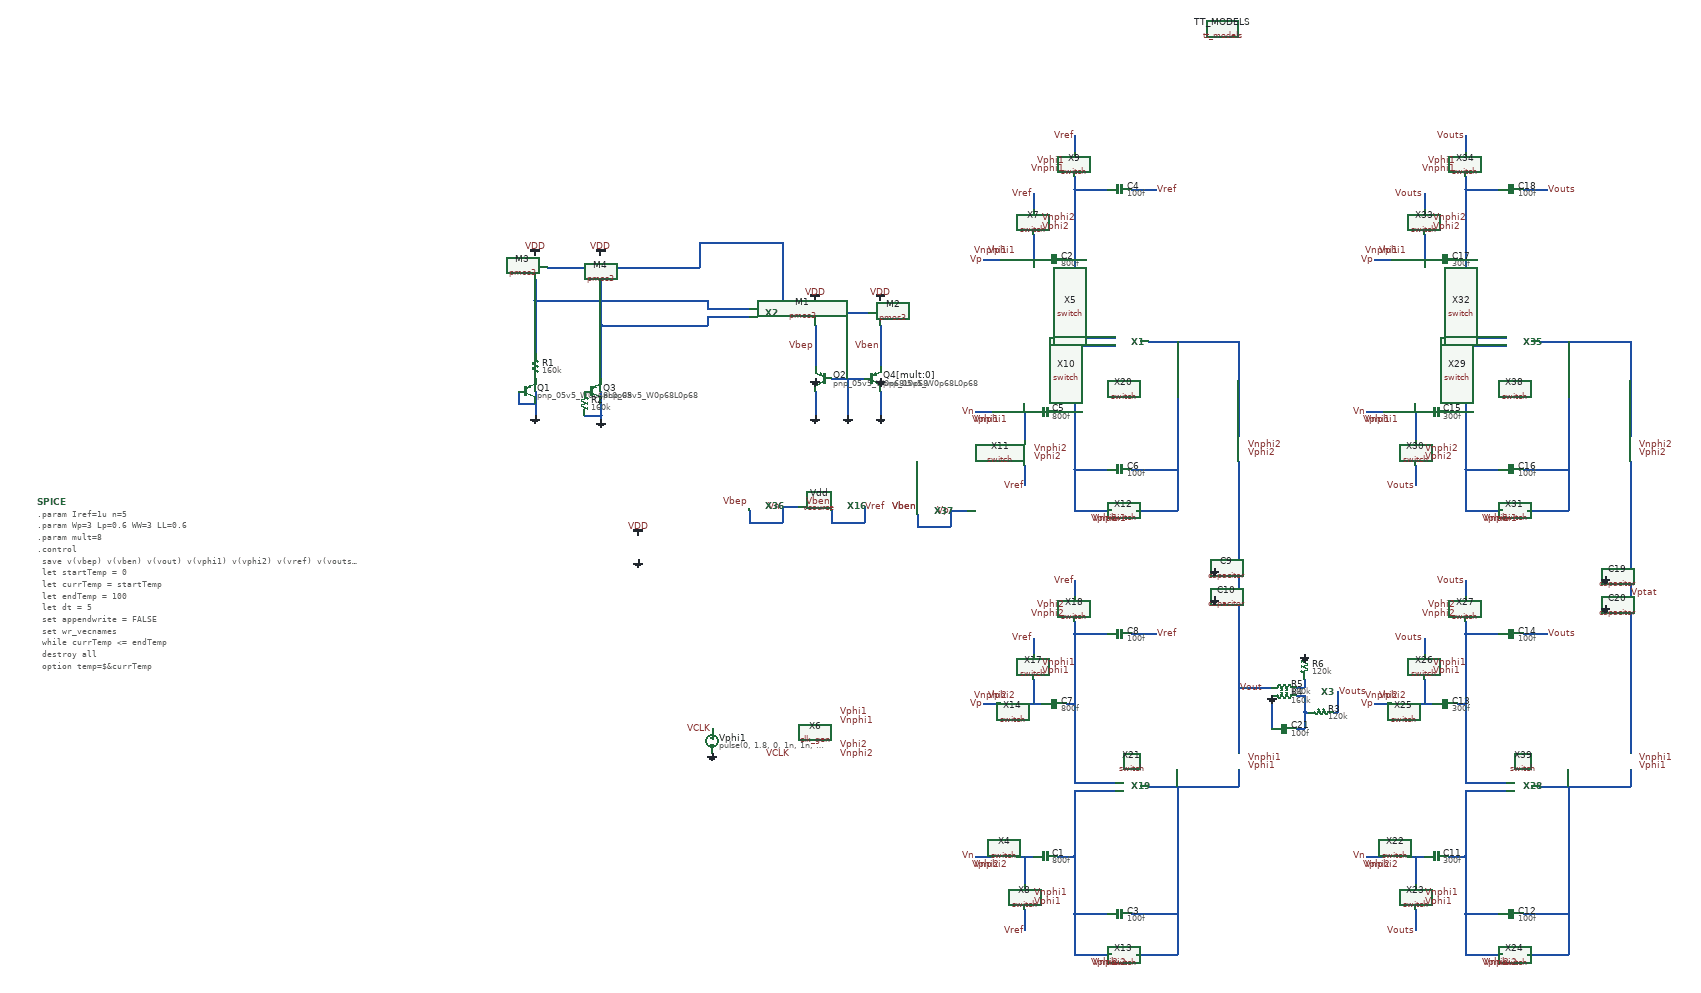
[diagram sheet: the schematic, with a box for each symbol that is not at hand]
v {xschem version=2.9.9 file_version=1.2 }
G {}
K {}
V {}
S {}
E {}
N 610 -70 670 -70 { lab=#net1}
N 410 10 410 40 { lab=Vnn}
N -60 -40 -60 -10 { lab=Vben}
N -60 -110 -60 -40 { lab=Vben}
N -220 -110 -220 -10 { lab=Vbep}
N -300 -140 -250 -140 { lab=#net2}
N -250 -140 -90 -140 { lab=#net2}
N -900 50 -900 80 { lab=GND}
N -940 50 -940 80 { lab=GND}
N -940 80 -900 80 { lab=GND}
N -900 80 -900 110 { lab=GND}
N -740 50 -740 80 { lab=GND}
N -740 80 -740 110 { lab=GND}
N -780 110 -740 110 { lab=GND}
N -740 110 -740 120 { lab=GND}
N -740 -110 -740 20 { lab=#net3}
N -740 -110 -480 -110 { lab=#net3}
N -900 -170 -480 -170 { lab=#net4}
N -900 -170 -900 -40 { lab=#net4}
N -500 -310 -500 -250 { lab=#net2}
N -500 -310 -300 -310 { lab=#net2}
N -300 -310 -300 -140 { lab=#net2}
N -870 -250 -710 -250 { lab=#net2}
N -710 -250 -500 -250 { lab=#net2}
N -740 -220 -740 -110 { lab=#net3}
N -900 -220 -900 -170 { lab=#net4}
N -180 20 -100 20 { lab=GND}
N -60 50 -60 110 { lab=GND}
N -220 50 -220 110 { lab=GND}
N -140 20 -140 80 { lab=GND}
N -140 80 -140 110 { lab=GND}
N 410 100 410 240 { lab=Vnn}
N 410 240 490 240 { lab=Vnn}
N 410 340 500 340 { lab=Vnn}
N 410 240 410 340 { lab=Vnn}
N 660 70 660 240 { lab=#net1}
N 550 240 660 240 { lab=#net1}
N 560 340 660 340 { lab=#net1}
N 660 240 660 340 { lab=#net1}
N 290 100 290 170 { lab=#net5}
N 270 100 310 100 { lab=#net5}
N 170 100 210 100 { lab=Vn}
N 290 230 290 280 { lab=Vref}
N 370 100 410 100 { lab=Vnn}
N 410 40 410 100 { lab=Vnn}
N 660 -70 660 70 { lab=#net1}
N 410 -440 410 -270 { lab=Vpp}
N 410 -440 490 -440 { lab=Vpp}
N 410 -470 410 -440 { lab=Vpp}
N 310 -330 310 -270 { lab=#net6}
N 290 -270 330 -270 { lab=#net6}
N 190 -270 230 -270 { lab=Vp}
N 550 -440 610 -440 { lab=Vref}
N 410 -570 410 -530 { lab=Vref}
N 310 -430 310 -390 { lab=Vref}
N 410 -40 410 10 { lab=Vnn}
N 410 -270 410 -100 { lab=Vpp}
N 390 -270 410 -270 { lab=Vpp}
N 410 -60 410 -40 { lab=Vnn}
N 410 -100 410 -80 { lab=Vpp}
N 590 -70 610 -70 { lab=#net1}
N -480 -150 -380 -150 { lab=#net4}
N -480 -170 -480 -150 { lab=#net4}
N -480 -130 -480 -110 { lab=#net3}
N -480 -130 -380 -130 { lab=#net3}
N 410 -60 510 -60 { lab=Vnn}
N 410 -80 510 -80 { lab=Vpp}
N -180 340 -180 370 { lab=Vref}
N -180 370 -100 370 { lab=Vref}
N -100 330 -100 370 { lab=Vref}
N 670 -70 720 -70 { lab=#net1}
N 610 1010 670 1010 { lab=#net7}
N 410 1090 410 1120 { lab=#net8}
N 410 1180 410 1320 { lab=#net8}
N 410 1320 490 1320 { lab=#net8}
N 410 1420 500 1420 { lab=#net8}
N 410 1320 410 1420 { lab=#net8}
N 660 1150 660 1320 { lab=#net7}
N 550 1320 660 1320 { lab=#net7}
N 560 1420 660 1420 { lab=#net7}
N 660 1320 660 1420 { lab=#net7}
N 290 1180 290 1250 { lab=#net9}
N 270 1180 310 1180 { lab=#net9}
N 170 1180 210 1180 { lab=Vn}
N 290 1310 290 1360 { lab=Vref}
N 370 1180 410 1180 { lab=#net8}
N 410 1120 410 1180 { lab=#net8}
N 660 1010 660 1150 { lab=#net7}
N 410 640 410 810 { lab=#net10}
N 410 640 490 640 { lab=#net10}
N 410 610 410 640 { lab=#net10}
N 310 750 310 810 { lab=#net11}
N 290 810 330 810 { lab=#net11}
N 190 810 230 810 { lab=Vp}
N 550 640 610 640 { lab=Vref}
N 410 510 410 550 { lab=Vref}
N 310 650 310 690 { lab=Vref}
N 410 1040 410 1090 { lab=#net8}
N 410 810 410 980 { lab=#net10}
N 390 810 410 810 { lab=#net10}
N 410 1020 410 1040 { lab=#net8}
N 410 980 410 1000 { lab=#net10}
N 590 1010 610 1010 { lab=#net7}
N 410 1020 510 1020 { lab=#net8}
N 410 1000 510 1000 { lab=#net10}
N 720 -70 810 -70 { lab=#net1}
N 810 -70 810 160 { lab=#net1}
N 810 220 810 810 { lab=Vout}
N 720 1010 810 1010 { lab=#net7}
N 810 970 810 1010 { lab=#net7}
N 810 810 810 930 { lab=Vout}
N 1560 1010 1620 1010 { lab=#net12}
N 1360 1090 1360 1120 { lab=#net13}
N 1360 1180 1360 1320 { lab=#net13}
N 1360 1320 1440 1320 { lab=#net13}
N 1360 1420 1450 1420 { lab=#net13}
N 1360 1320 1360 1420 { lab=#net13}
N 1610 1150 1610 1320 { lab=#net12}
N 1500 1320 1610 1320 { lab=#net12}
N 1510 1420 1610 1420 { lab=#net12}
N 1610 1320 1610 1420 { lab=#net12}
N 1240 1180 1240 1250 { lab=#net14}
N 1220 1180 1260 1180 { lab=#net14}
N 1120 1180 1160 1180 { lab=Vn}
N 1240 1310 1240 1360 { lab=Vouts}
N 1320 1180 1360 1180 { lab=#net13}
N 1360 1120 1360 1180 { lab=#net13}
N 1610 1010 1610 1150 { lab=#net12}
N 1360 640 1360 810 { lab=#net15}
N 1360 640 1440 640 { lab=#net15}
N 1360 610 1360 640 { lab=#net15}
N 1260 750 1260 810 { lab=#net16}
N 1240 810 1280 810 { lab=#net16}
N 1140 810 1180 810 { lab=Vp}
N 1500 640 1560 640 { lab=Vouts}
N 1360 510 1360 550 { lab=Vouts}
N 1260 650 1260 690 { lab=Vouts}
N 1360 1040 1360 1090 { lab=#net13}
N 1360 810 1360 980 { lab=#net15}
N 1340 810 1360 810 { lab=#net15}
N 1360 1020 1360 1040 { lab=#net13}
N 1360 980 1360 1000 { lab=#net15}
N 1540 1010 1560 1010 { lab=#net12}
N 1360 1020 1460 1020 { lab=#net13}
N 1360 1000 1460 1000 { lab=#net15}
N 670 1010 720 1010 { lab=#net7}
N 1560 -70 1620 -70 { lab=#net17}
N 1360 10 1360 40 { lab=#net18}
N 1360 100 1360 240 { lab=#net18}
N 1360 240 1440 240 { lab=#net18}
N 1360 340 1450 340 { lab=#net18}
N 1360 240 1360 340 { lab=#net18}
N 1610 70 1610 240 { lab=#net17}
N 1500 240 1610 240 { lab=#net17}
N 1510 340 1610 340 { lab=#net17}
N 1610 240 1610 340 { lab=#net17}
N 1240 100 1240 170 { lab=#net19}
N 1220 100 1260 100 { lab=#net19}
N 1120 100 1160 100 { lab=Vn}
N 1240 230 1240 280 { lab=Vouts}
N 1320 100 1360 100 { lab=#net18}
N 1360 40 1360 100 { lab=#net18}
N 1610 -70 1610 70 { lab=#net17}
N 1360 -440 1360 -270 { lab=#net20}
N 1360 -440 1440 -440 { lab=#net20}
N 1360 -470 1360 -440 { lab=#net20}
N 1260 -330 1260 -270 { lab=#net21}
N 1240 -270 1280 -270 { lab=#net21}
N 1140 -270 1180 -270 { lab=Vp}
N 1500 -440 1560 -440 { lab=Vouts}
N 1360 -570 1360 -530 { lab=Vouts}
N 1260 -430 1260 -390 { lab=Vouts}
N 1360 -40 1360 10 { lab=#net18}
N 1360 -270 1360 -100 { lab=#net20}
N 1340 -270 1360 -270 { lab=#net20}
N 1360 -60 1360 -40 { lab=#net18}
N 1360 -100 1360 -80 { lab=#net20}
N 1540 -70 1560 -70 { lab=#net17}
N 1360 -60 1460 -60 { lab=#net18}
N 1360 -80 1460 -80 { lab=#net20}
N 1620 -70 1670 -70 { lab=#net17}
N 1670 -70 1760 -70 { lab=#net17}
N 1760 -70 1760 160 { lab=#net17}
N 1760 220 1760 810 { lab=Vptat}
N 1760 970 1760 1010 { lab=#net12}
N 1760 810 1760 930 { lab=Vptat}
N 1620 1010 1760 1010 { lab=#net12}
N -300 330 -260 330 { lab=Vn}
N 110 340 150 340 { lab=Vp}
N -380 340 -380 370 { lab=Vn}
N -380 370 -300 370 { lab=Vn}
N -300 330 -300 370 { lab=Vn}
N 30 350 30 380 { lab=Vp}
N 30 380 110 380 { lab=Vp}
N 110 340 110 380 { lab=Vp}
N 1050 780 1050 830 { lab=Vouts}
N 1040 830 1050 830 { lab=Vouts}
N 970 830 980 830 { lab=#net22}
N 970 790 970 830 { lab=#net22}
N 950 790 970 790 { lab=#net22}
N 810 770 890 770 { lab=Vout}
N 950 770 970 770 { lab=#net23}
N 970 750 970 770 { lab=#net23}
N 890 790 890 870 { lab=GND}
N 950 870 970 870 { lab=#net22}
N 970 830 970 870 { lab=#net22}
C {madvlsi/vsource.sym} -650 430 0 0 {name=Vdd
value=1.8}
C {madvlsi/vdd.sym} -650 400 0 0 {name=l3 lab=VDD}
C {madvlsi/gnd.sym} -650 460 0 0 {name=l4 lab=GND}
C {devices/code_shown.sym} -2110 320 0 0 {name=SPICE only_toplevel=false value=".param Iref=1u n=5 
.param Wp=3 Lp=0.6 WW=3 LL=0.6
.param mult=8
.control
  save v(vbep) v(vben) v(vout) v(vphi1) v(vphi2) v(vref) v(vouts) v(vptat)
  let startTemp = 0
  let currTemp = startTemp
  let endTemp = 100
  let dt = 5
  set appendwrite = FALSE
  set wr_vecnames
  while currTemp <= endTemp
    destroy all
    option temp=$&currTemp
    tran 1.2u 60u
    wrdata /home/madvlsi/Documents/MADVLSI-Final_Project/schematic/data/SCbandgap\{$&currTemp\}ptat.csv v(vbep) v(vben) v(vout) v(vphi1) v(vphi2) v(vref) v(vouts) v(vptat) currTemp
    let currTemp = currTemp + dt
    reset
  end
*plot v(Vout) 8.0*(v(Vbep)-v(Vben))+v(Vben)
*plot v(Vout) v(Vouts)
.endc
.OPTIONS ITL1=300  ITL2=100"}
C {sky130_fd_pr/pnp_05v5.sym} -200 20 0 1 {name=Q2
model=pnp_05v5_W0p68L0p68
spiceprefix=X
}
C {madvlsi/vdd.sym} -220 -170 0 0 {name=l2 lab=VDD}
C {madvlsi/vdd.sym} -60 -170 0 0 {name=l5 lab=VDD}
C {devices/lab_pin.sym} -220 -60 0 0 {name=l10 sig_type=std_logic lab=Vbep}
C {devices/lab_pin.sym} -60 -60 0 0 {name=l11 sig_type=std_logic lab=Vben}
C {madvlsi/pmos3.sym} -220 -140 0 0 {name=M1
L=Lp
W=Wp
body=VDD
nf=1
mult=mult
ad="'int((nf+1)/2) * W/nf * 0.29'" 
pd="'2*int((nf+1)/2) * (W/nf + 0.29)'"
as="'int((nf+2)/2) * W/nf * 0.29'" 
ps="'2*int((nf+2)/2) * (W/nf + 0.29)'"
nrd="'0.29 / W'" nrs="'0.29 / W'"
sa=0 sb=0 sd=0
model=pfet_01v8
spiceprefix=X
}
C {madvlsi/pmos3.sym} -60 -140 0 0 {name=M2
L=Lp
W=Wp
body=VDD
nf=1
mult=1
ad="'int((nf+1)/2) * W/nf * 0.29'" 
pd="'2*int((nf+1)/2) * (W/nf + 0.29)'"
as="'int((nf+2)/2) * W/nf * 0.29'" 
ps="'2*int((nf+2)/2) * (W/nf + 0.29)'"
nrd="'0.29 / W'" nrs="'0.29 / W'"
sa=0 sb=0 sd=0
model=pfet_01v8
spiceprefix=X
}
C {sky130_fd_pr/pnp_05v5.sym} -80 20 0 0 {name=Q4[mult:0]
model=pnp_05v5_W0p68L0p68
spiceprefix=X
}
C {sky130_fd_pr/pnp_05v5.sym} -920 50 0 0 {name=Q1
model=pnp_05v5_W0p68L0p68
spiceprefix=X
}
C {madvlsi/gnd.sym} -900 110 0 0 {name=l19 lab=GND}
C {sky130_fd_pr/pnp_05v5.sym} -760 50 0 0 {name=Q3
model=pnp_05v5_W0p68L0p68
spiceprefix=X
}
C {madvlsi/gnd.sym} -740 120 0 0 {name=l20 lab=GND}
C {madvlsi/resistor.sym} -900 -10 0 0 {name=R1
value=160k
m=1}
C {madvlsi/resistor.sym} -780 80 0 0 {name=R2
value=160k
m=mult}
C {madvlsi/pmos3.sym} -900 -250 0 1 {name=M3
L=Lp
W=Wp
body=VDD
nf=1
mult=1
ad="'int((nf+1)/2) * W/nf * 0.29'" 
pd="'2*int((nf+1)/2) * (W/nf + 0.29)'"
as="'int((nf+2)/2) * W/nf * 0.29'" 
ps="'2*int((nf+2)/2) * (W/nf + 0.29)'"
nrd="'0.29 / W'" nrs="'0.29 / W'"
sa=0 sb=0 sd=0
model=pfet_01v8
spiceprefix=X
}
C {madvlsi/pmos3.sym} -740 -250 0 1 {name=M4
L=Lp
W=Wp
body=VDD
nf=1
mult=mult
ad="'int((nf+1)/2) * W/nf * 0.29'" 
pd="'2*int((nf+1)/2) * (W/nf + 0.29)'"
as="'int((nf+2)/2) * W/nf * 0.29'" 
ps="'2*int((nf+2)/2) * (W/nf + 0.29)'"
nrd="'0.29 / W'" nrs="'0.29 / W'"
sa=0 sb=0 sd=0
model=pfet_01v8
spiceprefix=X
}
C {madvlsi/vdd.sym} -740 -280 0 0 {name=l21 lab=VDD}
C {madvlsi/vdd.sym} -900 -280 0 0 {name=l22 lab=VDD}
C {madvlsi/gnd.sym} -220 20 1 1 {name=l25 lab=GND}
C {madvlsi/gnd.sym} -60 20 3 1 {name=l26 lab=GND}
C {madvlsi/gnd.sym} -60 110 0 1 {name=l27 lab=GND}
C {madvlsi/gnd.sym} -220 110 0 1 {name=l28 lab=GND}
C {madvlsi/gnd.sym} -140 110 0 1 {name=l29 lab=GND}
C {devices/lab_pin.sym} 410 -140 0 0 {name=l6 sig_type=std_logic lab=Vpp}
C {devices/lab_pin.sym} 410 10 0 0 {name=l13 sig_type=std_logic lab=Vnn}
C {madvlsi/capacitor.sym} 340 100 1 0 {name=C5
value=800f
m=1}
C {madvlsi/capacitor.sym} 520 240 1 0 {name=C6
value=100f
m=1}
C {/home/madvlsi/Documents/MADVLSI-Final_Project/schematic/switch.sym} 240 100 0 0 {name=X10}
C {/home/madvlsi/Documents/MADVLSI-Final_Project/schematic/switch.sym} 290 200 3 0 {name=X11}
C {/home/madvlsi/Documents/MADVLSI-Final_Project/schematic/switch.sym} 530 340 0 0 {name=X12}
C {devices/lab_pin.sym} 290 280 3 0 {name=l1 sig_type=std_logic lab=Vref}
C {devices/lab_pin.sym} 520 360 3 0 {name=l31 sig_type=std_logic lab=Vphi1}
C {devices/lab_pin.sym} 540 360 3 0 {name=l32 sig_type=std_logic lab=Vnphi1}
C {devices/lab_pin.sym} 230 120 3 0 {name=l33 sig_type=std_logic lab=Vphi1}
C {devices/lab_pin.sym} 250 120 3 0 {name=l50 sig_type=std_logic lab=Vnphi1}
C {devices/lab_pin.sym} 310 210 2 0 {name=l51 sig_type=std_logic lab=Vphi2}
C {madvlsi/capacitor.sym} 360 -270 1 0 {name=C2
value=800f
m=1}
C {madvlsi/capacitor.sym} 520 -440 1 0 {name=C4
value=100f
m=1}
C {/home/madvlsi/Documents/MADVLSI-Final_Project/schematic/switch.sym} 260 -270 2 0 {name=X5}
C {/home/madvlsi/Documents/MADVLSI-Final_Project/schematic/switch.sym} 310 -360 3 0 {name=X7}
C {/home/madvlsi/Documents/MADVLSI-Final_Project/schematic/switch.sym} 410 -500 1 0 {name=X9}
C {devices/lab_pin.sym} 410 -570 1 0 {name=l36 sig_type=std_logic lab=Vref}
C {devices/lab_pin.sym} 310 -430 1 0 {name=l38 sig_type=std_logic lab=Vref}
C {devices/lab_pin.sym} 270 -290 1 0 {name=l44 sig_type=std_logic lab=Vphi1}
C {devices/lab_pin.sym} 250 -290 1 0 {name=l49 sig_type=std_logic lab=Vnphi1}
C {devices/lab_pin.sym} 330 -350 2 0 {name=l52 sig_type=std_logic lab=Vphi2}
C {devices/lab_pin.sym} 330 -370 2 0 {name=l53 sig_type=std_logic lab=Vnphi2}
C {devices/lab_pin.sym} 610 -440 2 0 {name=l54 sig_type=std_logic lab=Vref}
C {devices/lab_pin.sym} -100 330 2 0 {name=l56 sig_type=std_logic lab=Vref}
C {madvlsi/vsource.sym} -470 900 0 0 {name=Vphi1
value="pulse(0, 1.8, 0, 1n, 1n, 6u, 12u)"}
C {madvlsi/gnd.sym} -470 930 0 0 {name=l30 lab=GND}
C {devices/lab_pin.sym} -160 830 2 0 {name=l58 sig_type=std_logic lab=Vphi1}
C {devices/lab_pin.sym} -160 850 2 0 {name=l62 sig_type=std_logic lab=Vnphi1}
C {devices/lab_pin.sym} -160 930 2 0 {name=l68 sig_type=std_logic lab=Vnphi2}
C {devices/lab_pin.sym} 310 190 2 0 {name=l34 sig_type=std_logic lab=Vnphi2}
C {devices/lab_pin.sym} 190 -270 1 0 {name=l35 sig_type=std_logic lab=Vp}
C {devices/lab_pin.sym} 170 100 1 0 {name=l37 sig_type=std_logic lab=Vn}
C {devices/lab_pin.sym} 390 -510 0 0 {name=l39 sig_type=std_logic lab=Vphi1}
C {devices/lab_pin.sym} 390 -490 0 0 {name=l40 sig_type=std_logic lab=Vnphi1}
C {/home/madvlsi/Documents/MADVLSI-Final_Project/schematic/selfbiasedcascode2stage.sym} -340 -140 0 0 {name=X2}
C {/home/madvlsi/Documents/MADVLSI-Final_Project/schematic/selfbiasedcascode2stage.sym} 550 -70 0 0 {name=X1}
C {/home/madvlsi/Documents/MADVLSI-Final_Project/schematic/selfbiasedcascode2stage.sym} -140 330 0 0 {name=X16}
C {devices/lab_pin.sym} -180 320 0 0 {name=l15 sig_type=std_logic lab=Vben}
C {madvlsi/tt_models.sym} 770 -830 0 0 {
name=TT_MODELS
only_toplevel=false
value=".option wnflag=1
.param MC_SWITCH=0.0
.lib /media/qdeng/526448C32060CF5C/skywater/skywater-pdk/libraries/sky130_fd_pr_ngspice/latest/models/sky130.lib.spice tt"
}
C {/home/madvlsi/Documents/MADVLSI-Final_Project/schematic/clk_gen.sym} -220 880 0 0 {name=X6 Wp=1 Lp=0.15 WW=1 LL=0.15}
C {devices/lab_pin.sym} -160 910 2 0 {name=l7 sig_type=std_logic lab=Vphi2}
C {devices/lab_pin.sym} -470 870 1 0 {name=l16 sig_type=std_logic lab=VCLK}
C {devices/lab_pin.sym} -280 930 0 0 {name=l17 sig_type=std_logic lab=VCLK}
C {devices/lab_pin.sym} 810 770 2 0 {name=l18 sig_type=std_logic lab=Vout}
C {madvlsi/capacitor.sym} 340 1180 1 0 {name=C1
value=800f
m=1}
C {madvlsi/capacitor.sym} 520 1320 1 0 {name=C3
value=100f
m=1}
C {/home/madvlsi/Documents/MADVLSI-Final_Project/schematic/switch.sym} 240 1180 0 0 {name=X4}
C {/home/madvlsi/Documents/MADVLSI-Final_Project/schematic/switch.sym} 290 1280 3 0 {name=X8}
C {/home/madvlsi/Documents/MADVLSI-Final_Project/schematic/switch.sym} 530 1420 0 0 {name=X13}
C {devices/lab_pin.sym} 290 1360 3 0 {name=l41 sig_type=std_logic lab=Vref}
C {devices/lab_pin.sym} 520 1440 3 0 {name=l42 sig_type=std_logic lab=Vphi2}
C {devices/lab_pin.sym} 540 1440 3 0 {name=l43 sig_type=std_logic lab=Vnphi2}
C {devices/lab_pin.sym} 230 1200 3 0 {name=l45 sig_type=std_logic lab=Vphi2}
C {devices/lab_pin.sym} 250 1200 3 0 {name=l46 sig_type=std_logic lab=Vnphi2}
C {devices/lab_pin.sym} 310 1290 2 0 {name=l47 sig_type=std_logic lab=Vphi1}
C {madvlsi/capacitor.sym} 360 810 1 0 {name=C7
value=800f
m=1}
C {madvlsi/capacitor.sym} 520 640 1 0 {name=C8
value=100f
m=1}
C {/home/madvlsi/Documents/MADVLSI-Final_Project/schematic/switch.sym} 260 810 2 0 {name=X14}
C {/home/madvlsi/Documents/MADVLSI-Final_Project/schematic/switch.sym} 310 720 3 0 {name=X17}
C {/home/madvlsi/Documents/MADVLSI-Final_Project/schematic/switch.sym} 410 580 1 0 {name=X18}
C {devices/lab_pin.sym} 410 510 1 0 {name=l48 sig_type=std_logic lab=Vref}
C {devices/lab_pin.sym} 310 650 1 0 {name=l55 sig_type=std_logic lab=Vref}
C {devices/lab_pin.sym} 270 790 1 0 {name=l57 sig_type=std_logic lab=Vphi2}
C {devices/lab_pin.sym} 250 790 1 0 {name=l59 sig_type=std_logic lab=Vnphi2}
C {devices/lab_pin.sym} 330 730 2 0 {name=l60 sig_type=std_logic lab=Vphi1}
C {devices/lab_pin.sym} 330 710 2 0 {name=l61 sig_type=std_logic lab=Vnphi1}
C {devices/lab_pin.sym} 610 640 2 0 {name=l63 sig_type=std_logic lab=Vref}
C {devices/lab_pin.sym} 310 1270 2 0 {name=l64 sig_type=std_logic lab=Vnphi1}
C {devices/lab_pin.sym} 190 810 1 0 {name=l65 sig_type=std_logic lab=Vp}
C {devices/lab_pin.sym} 170 1180 1 0 {name=l66 sig_type=std_logic lab=Vn}
C {devices/lab_pin.sym} 390 570 0 0 {name=l67 sig_type=std_logic lab=Vphi2}
C {devices/lab_pin.sym} 390 590 0 0 {name=l69 sig_type=std_logic lab=Vnphi2}
C {/home/madvlsi/Documents/MADVLSI-Final_Project/schematic/selfbiasedcascode2stage.sym} 550 1010 0 0 {name=X19}
C {/home/madvlsi/Documents/MADVLSI-Final_Project/schematic/switch.sym} 810 190 3 0 {name=X20}
C {devices/lab_pin.sym} 830 200 2 0 {name=l70 sig_type=std_logic lab=Vphi2}
C {devices/lab_pin.sym} 830 180 2 0 {name=l71 sig_type=std_logic lab=Vnphi2}
C {/home/madvlsi/Documents/MADVLSI-Final_Project/schematic/switch.sym} 810 950 3 0 {name=X21}
C {devices/lab_pin.sym} 830 960 2 0 {name=l72 sig_type=std_logic lab=Vphi1}
C {devices/lab_pin.sym} 830 940 2 0 {name=l73 sig_type=std_logic lab=Vnphi1}
C {madvlsi/capacitor.sym} 780 480 1 0 {name=C9
value=800f
m=1}
C {madvlsi/gnd.sym} 750 480 1 1 {name=l12 lab=GND}
C {madvlsi/capacitor.sym} 780 550 1 0 {name=C10
value=800f
m=1}
C {madvlsi/gnd.sym} 750 550 1 1 {name=l23 lab=GND}
C {madvlsi/capacitor.sym} 1290 1180 1 0 {name=C11
value=300f
m=1}
C {madvlsi/capacitor.sym} 1470 1320 1 0 {name=C12
value=100f
m=1}
C {/home/madvlsi/Documents/MADVLSI-Final_Project/schematic/switch.sym} 1190 1180 0 0 {name=X22}
C {/home/madvlsi/Documents/MADVLSI-Final_Project/schematic/switch.sym} 1240 1280 3 0 {name=X23}
C {/home/madvlsi/Documents/MADVLSI-Final_Project/schematic/switch.sym} 1480 1420 0 0 {name=X24}
C {devices/lab_pin.sym} 1470 1440 3 0 {name=l74 sig_type=std_logic lab=Vphi2}
C {devices/lab_pin.sym} 1490 1440 3 0 {name=l75 sig_type=std_logic lab=Vnphi2}
C {devices/lab_pin.sym} 1180 1200 3 0 {name=l76 sig_type=std_logic lab=Vphi2}
C {devices/lab_pin.sym} 1200 1200 3 0 {name=l77 sig_type=std_logic lab=Vnphi2}
C {devices/lab_pin.sym} 1260 1290 2 0 {name=l78 sig_type=std_logic lab=Vphi1}
C {madvlsi/capacitor.sym} 1310 810 1 0 {name=C13
value=300f
m=1}
C {madvlsi/capacitor.sym} 1470 640 1 0 {name=C14
value=100f
m=1}
C {/home/madvlsi/Documents/MADVLSI-Final_Project/schematic/switch.sym} 1210 810 2 0 {name=X25}
C {/home/madvlsi/Documents/MADVLSI-Final_Project/schematic/switch.sym} 1260 720 3 0 {name=X26}
C {/home/madvlsi/Documents/MADVLSI-Final_Project/schematic/switch.sym} 1360 580 1 0 {name=X27}
C {devices/lab_pin.sym} 1220 790 1 0 {name=l81 sig_type=std_logic lab=Vphi2}
C {devices/lab_pin.sym} 1200 790 1 0 {name=l82 sig_type=std_logic lab=Vnphi2}
C {devices/lab_pin.sym} 1280 730 2 0 {name=l83 sig_type=std_logic lab=Vphi1}
C {devices/lab_pin.sym} 1280 710 2 0 {name=l84 sig_type=std_logic lab=Vnphi1}
C {devices/lab_pin.sym} 1260 1270 2 0 {name=l86 sig_type=std_logic lab=Vnphi1}
C {devices/lab_pin.sym} 1140 810 1 0 {name=l87 sig_type=std_logic lab=Vp}
C {devices/lab_pin.sym} 1120 1180 1 0 {name=l88 sig_type=std_logic lab=Vn}
C {devices/lab_pin.sym} 1340 570 0 0 {name=l89 sig_type=std_logic lab=Vphi2}
C {devices/lab_pin.sym} 1340 590 0 0 {name=l90 sig_type=std_logic lab=Vnphi2}
C {/home/madvlsi/Documents/MADVLSI-Final_Project/schematic/selfbiasedcascode2stage.sym} 1500 1010 0 0 {name=X28}
C {devices/lab_pin.sym} 1240 1360 3 0 {name=l24 sig_type=std_logic lab=Vouts}
C {devices/lab_pin.sym} 1560 640 2 0 {name=l79 sig_type=std_logic lab=Vouts}
C {devices/lab_pin.sym} 1360 510 1 0 {name=l80 sig_type=std_logic lab=Vouts}
C {devices/lab_pin.sym} 1260 650 1 0 {name=l85 sig_type=std_logic lab=Vouts}
C {madvlsi/capacitor.sym} 1290 100 1 0 {name=C15
value=300f
m=1}
C {madvlsi/capacitor.sym} 1470 240 1 0 {name=C16
value=100f
m=1}
C {/home/madvlsi/Documents/MADVLSI-Final_Project/schematic/switch.sym} 1190 100 0 0 {name=X29}
C {/home/madvlsi/Documents/MADVLSI-Final_Project/schematic/switch.sym} 1240 200 3 0 {name=X30}
C {/home/madvlsi/Documents/MADVLSI-Final_Project/schematic/switch.sym} 1480 340 0 0 {name=X31}
C {devices/lab_pin.sym} 1470 360 3 0 {name=l94 sig_type=std_logic lab=Vphi1}
C {devices/lab_pin.sym} 1490 360 3 0 {name=l95 sig_type=std_logic lab=Vnphi1}
C {devices/lab_pin.sym} 1180 120 3 0 {name=l96 sig_type=std_logic lab=Vphi1}
C {devices/lab_pin.sym} 1200 120 3 0 {name=l97 sig_type=std_logic lab=Vnphi1}
C {devices/lab_pin.sym} 1260 210 2 0 {name=l98 sig_type=std_logic lab=Vphi2}
C {madvlsi/capacitor.sym} 1310 -270 1 0 {name=C17
value=300f
m=1}
C {madvlsi/capacitor.sym} 1470 -440 1 0 {name=C18
value=100f
m=1}
C {/home/madvlsi/Documents/MADVLSI-Final_Project/schematic/switch.sym} 1210 -270 2 0 {name=X32}
C {/home/madvlsi/Documents/MADVLSI-Final_Project/schematic/switch.sym} 1260 -360 3 0 {name=X33}
C {/home/madvlsi/Documents/MADVLSI-Final_Project/schematic/switch.sym} 1360 -500 1 0 {name=X34}
C {devices/lab_pin.sym} 1220 -290 1 0 {name=l101 sig_type=std_logic lab=Vphi1}
C {devices/lab_pin.sym} 1200 -290 1 0 {name=l102 sig_type=std_logic lab=Vnphi1}
C {devices/lab_pin.sym} 1280 -350 2 0 {name=l103 sig_type=std_logic lab=Vphi2}
C {devices/lab_pin.sym} 1280 -370 2 0 {name=l104 sig_type=std_logic lab=Vnphi2}
C {devices/lab_pin.sym} 1260 190 2 0 {name=l106 sig_type=std_logic lab=Vnphi2}
C {devices/lab_pin.sym} 1140 -270 1 0 {name=l107 sig_type=std_logic lab=Vp}
C {devices/lab_pin.sym} 1120 100 1 0 {name=l108 sig_type=std_logic lab=Vn}
C {devices/lab_pin.sym} 1340 -510 0 0 {name=l109 sig_type=std_logic lab=Vphi1}
C {devices/lab_pin.sym} 1340 -490 0 0 {name=l110 sig_type=std_logic lab=Vnphi1}
C {/home/madvlsi/Documents/MADVLSI-Final_Project/schematic/selfbiasedcascode2stage.sym} 1500 -70 0 0 {name=X35}
C {/home/madvlsi/Documents/MADVLSI-Final_Project/schematic/switch.sym} 1760 190 3 0 {name=X38}
C {devices/lab_pin.sym} 1780 200 2 0 {name=l114 sig_type=std_logic lab=Vphi2}
C {devices/lab_pin.sym} 1780 180 2 0 {name=l115 sig_type=std_logic lab=Vnphi2}
C {/home/madvlsi/Documents/MADVLSI-Final_Project/schematic/switch.sym} 1760 950 3 0 {name=X39}
C {devices/lab_pin.sym} 1780 960 2 0 {name=l116 sig_type=std_logic lab=Vphi1}
C {devices/lab_pin.sym} 1780 940 2 0 {name=l117 sig_type=std_logic lab=Vnphi1}
C {madvlsi/capacitor.sym} 1730 500 1 0 {name=C19
value=800f
m=1}
C {madvlsi/gnd.sym} 1700 500 1 1 {name=l118 lab=GND}
C {madvlsi/capacitor.sym} 1730 570 1 0 {name=C20
value=800f
m=1}
C {madvlsi/gnd.sym} 1700 570 1 1 {name=l119 lab=GND}
C {devices/lab_pin.sym} 1760 540 2 0 {name=l120 sig_type=std_logic lab=Vptat}
C {devices/lab_pin.sym} 1260 -430 1 0 {name=l93 sig_type=std_logic lab=Vouts}
C {devices/lab_pin.sym} 1360 -570 1 0 {name=l99 sig_type=std_logic lab=Vouts}
C {devices/lab_pin.sym} 1560 -440 2 0 {name=l100 sig_type=std_logic lab=Vouts}
C {devices/lab_pin.sym} 1240 280 3 0 {name=l105 sig_type=std_logic lab=Vouts}
C {devices/lab_pin.sym} 110 340 1 0 {name=l91 sig_type=std_logic lab=Vp}
C {devices/lab_pin.sym} -300 330 1 0 {name=l92 sig_type=std_logic lab=Vn}
C {/home/madvlsi/Documents/MADVLSI-Final_Project/schematic/selfbiasedcascode2stage.sym} -340 330 0 0 {name=X36}
C {devices/lab_pin.sym} -380 320 0 0 {name=l111 sig_type=std_logic lab=Vbep}
C {devices/lab_pin.sym} 30 330 0 0 {name=l112 sig_type=std_logic lab=Vben}
C {/home/madvlsi/Documents/MADVLSI-Final_Project/schematic/selfbiasedcascode2stage.sym} 70 340 0 0 {name=X37}
C {devices/lab_pin.sym} 30 330 0 0 {name=l113 sig_type=std_logic lab=Vben}
C {/home/madvlsi/Documents/MADVLSI-Final_Project/schematic/selfbiasedcascode2stage.sym} 1010 780 0 0 {name=X3}
C {madvlsi/resistor.sym} 1010 830 1 0 {name=R3
value=120k
m=1}
C {madvlsi/resistor.sym} 920 790 1 0 {name=R4
value=160k
m=1}
C {madvlsi/capacitor.sym} 920 870 3 0 {name=C21
value=100f
m=1}
C {devices/lab_pin.sym} 1050 780 2 0 {name=l9 sig_type=std_logic lab=Vouts}
C {madvlsi/resistor.sym} 920 770 3 0 {name=R5
value=160k
m=1}
C {madvlsi/resistor.sym} 970 720 2 0 {name=R6
value=120k
m=1}
C {madvlsi/gnd.sym} 970 690 2 1 {name=l8 lab=GND}
C {madvlsi/gnd.sym} 890 790 1 1 {name=l14 lab=GND}
